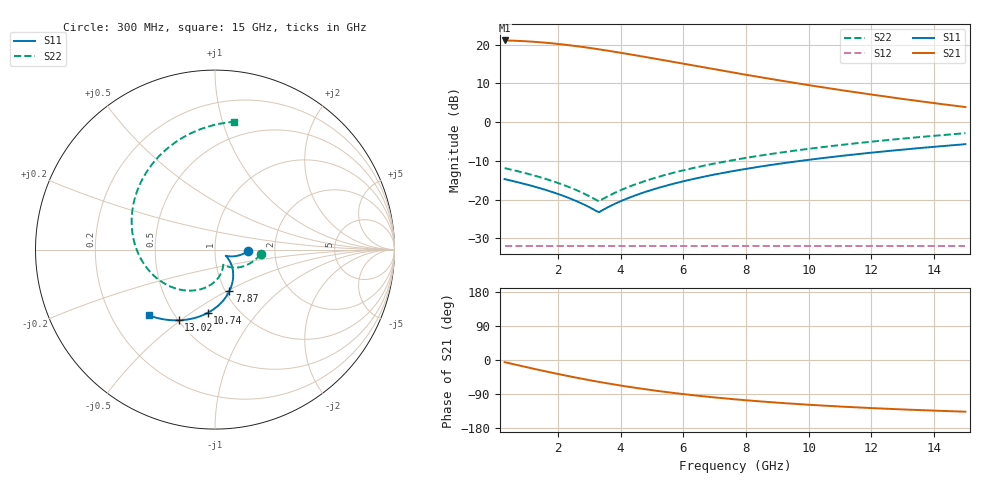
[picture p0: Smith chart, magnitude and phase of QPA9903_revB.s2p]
! written by passband
# GHZ S MA R 50
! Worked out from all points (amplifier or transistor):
!   201 points, 300 MHz to 15 GHz, reference 50 ohm
!   highest |S21| = 21.1 dB at 300 MHz (marker M1)
!   |S21| within 3 dB of that: start of sweep to 3.87 GHz
!   unconditionally stable (mu >= 1): start of sweep to end of sweep
!   at 2.725 GHz: K = 2.18, MAG = 19.6 dB, |S12| = -32.0 dB
!   at 7.65 GHz: K = 3.98, MAG = 13.4 dB, |S12| = -32.0 dB
!   at 15 GHz: K = 4.86, MAG = 8.1 dB, |S12| = -32.0 dB
!   S11 on the Smith chart (normalised r, x): 300 MHz: 1.45, -0.03; 7.87 GHz: 1.05, -0.51; 10.74 GHz: 0.72, -0.58; 13.02 GHz: 0.50, -0.49; 15 GHz: 0.36, -0.37
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0.3  0.1841 -2.7  11.32 -5.7  0.02512 -9.2  0.2553 -5.6
0.594  0.1728 -5.3  11.24 -11.3  0.02512 -18.3  0.2395 -11.0
0.888  0.1615 -8.0  11.11 -16.8  0.02512 -27.3  0.2238 -16.5
1.2555  0.1473 -11.3  10.87 -23.6  0.02512 -38.6  0.2042 -23.3
1.623  0.1331 -14.6  10.58 -30.3  0.02512 -49.9  0.1846 -30.1
2.211  0.1105 -19.9  9.993 -40.5  0.02512 -68.0  0.1531 -41.1
2.799  0.0878 -25.2  9.322 -50.0  0.02512 -86.1  0.1217 -52.0
3.3135  0.06901 -29.8  8.698 -57.8  0.02512 -102.0  0.09567 -61.5
3.828  0.08884 -34.5  8.067 -65.1  0.02512 -117.8  0.1232 -71.1
4.4895  0.1143 -40.4  7.276 -73.6  0.02512 -138.1  0.1585 -83.4
5.2245  0.1427 -47.0  6.456 -82.1  0.02512 -160.8  0.1978 -97.0
5.739  0.1625 -51.7  5.927 -87.5  0.02512 -176.6  0.2253 -106.6
6.327  0.1852 -57.0  5.374 -93.0  0.02512 165.3  0.2567 -117.5
6.9885  0.2107 -62.9  4.816 -98.7  0.02512 145.0  0.292 -129.8
7.65  0.2362 -68.9  4.323 -103.8  0.02512 124.6  0.3274 -142.1
7.8705  0.2447 -70.8  4.172 -105.4  0.02512 117.8  0.3392 -146.2
8.8995  0.2843 -80.1  3.547 -112.0  0.02512 86.2  0.3942 -165.3
10.149  0.3325 -91.4  2.94 -118.8  0.02512 47.7  0.4609 171.5
10.737  0.3551 -96.6  2.701 -121.6  0.02512 29.6  0.4923 160.6
12.5745  0.426 -113.2  2.105 -129.0  0.02512 -26.9  0.5905 126.5
13.0155  0.443 -117.2  1.989 -130.5  0.02512 -40.5  0.6141 118.3
15  0.5194 -135.0  1.566 -136.4  0.02512 -101.6  0.7201 81.5
